One B-rep face of a CAD part: STEP entity #385.
In plain terms, the planar face has unit normal (1, 0, 0).
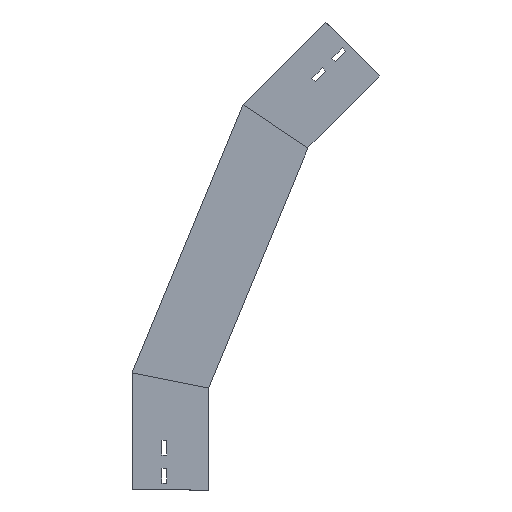
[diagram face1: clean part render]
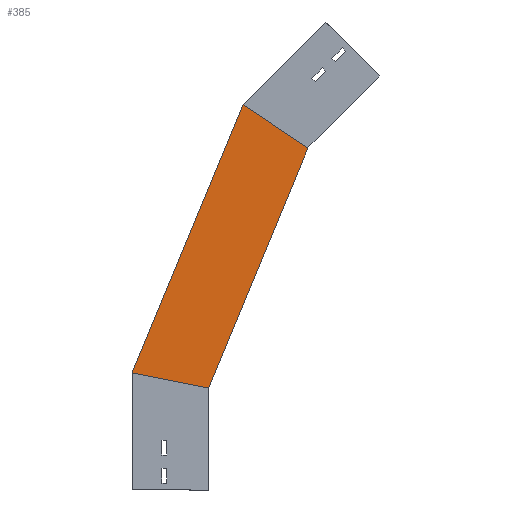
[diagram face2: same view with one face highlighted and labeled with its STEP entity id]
Its self-contained STEP definition (entity closure, numbers rounded to 3 decimals):
#101 = DIRECTION ( 'NONE',  ( 0., -0.383, 0.924 ) ) ;
#175 = AXIS2_PLACEMENT_3D ( 'NONE', #929, #949, #1419 ) ;
#190 = VECTOR ( 'NONE', #1260, 1000. ) ;
#210 = LINE ( 'NONE', #659, #600 ) ;
#240 = ORIENTED_EDGE ( 'NONE', *, *, #1238, .T. ) ;
#261 = CARTESIAN_POINT ( 'NONE',  ( 0., 113.395, 170.218 ) ) ;
#363 = ORIENTED_EDGE ( 'NONE', *, *, #1202, .T. ) ;
#373 = DIRECTION ( 'NONE',  ( 0., -0.383, 0.924 ) ) ;
#385 = ADVANCED_FACE ( 'NONE', ( #1169 ), #489, .T. ) ;
#401 = EDGE_LOOP ( 'NONE', ( #363, #240, #548, #973 ) ) ;
#412 = VECTOR ( 'NONE', #959, 1000. ) ;
#481 = VERTEX_POINT ( 'NONE', #704 ) ;
#489 = PLANE ( 'NONE',  #175 ) ;
#548 = ORIENTED_EDGE ( 'NONE', *, *, #695, .F. ) ;
#591 = CARTESIAN_POINT ( 'NONE',  ( 0., -146.568, 503.846 ) ) ;
#600 = VECTOR ( 'NONE', #101, 1000. ) ;
#659 = CARTESIAN_POINT ( 'NONE',  ( 0., 9.458, 127.166 ) ) ;
#691 = LINE ( 'NONE', #932, #190 ) ;
#695 = EDGE_CURVE ( 'NONE', #1444, #1204, #210, .T. ) ;
#704 = CARTESIAN_POINT ( 'NONE',  ( 0., 112.5, 172.378 ) ) ;
#757 = CARTESIAN_POINT ( 'NONE',  ( 0., -51.195, 567.572 ) ) ;
#894 = CARTESIAN_POINT ( 'NONE',  ( 0., 0., 150. ) ) ;
#929 = CARTESIAN_POINT ( 'NONE',  ( 0., 9.458, 127.166 ) ) ;
#932 = CARTESIAN_POINT ( 'NONE',  ( 0., -28.701, 144.291 ) ) ;
#946 = VERTEX_POINT ( 'NONE', #757 ) ;
#949 = DIRECTION ( 'NONE',  ( 1., 0., 0. ) ) ;
#959 = DIRECTION ( 'NONE',  ( 0., -0.831, -0.556 ) ) ;
#973 = ORIENTED_EDGE ( 'NONE', *, *, #1003, .F. ) ;
#1003 = EDGE_CURVE ( 'NONE', #481, #1444, #691, .T. ) ;
#1068 = LINE ( 'NONE', #1318, #412 ) ;
#1071 = VECTOR ( 'NONE', #373, 1000. ) ;
#1169 = FACE_OUTER_BOUND ( 'NONE', #401, .T. ) ;
#1179 = LINE ( 'NONE', #261, #1071 ) ;
#1202 = EDGE_CURVE ( 'NONE', #481, #946, #1179, .T. ) ;
#1204 = VERTEX_POINT ( 'NONE', #591 ) ;
#1238 = EDGE_CURVE ( 'NONE', #946, #1204, #1068, .T. ) ;
#1260 = DIRECTION ( 'NONE',  ( 0., -0.981, -0.195 ) ) ;
#1318 = CARTESIAN_POINT ( 'NONE',  ( 0., -212.704, 459.655 ) ) ;
#1419 = DIRECTION ( 'NONE',  ( 0., 0., -1. ) ) ;
#1444 = VERTEX_POINT ( 'NONE', #894 ) ;
